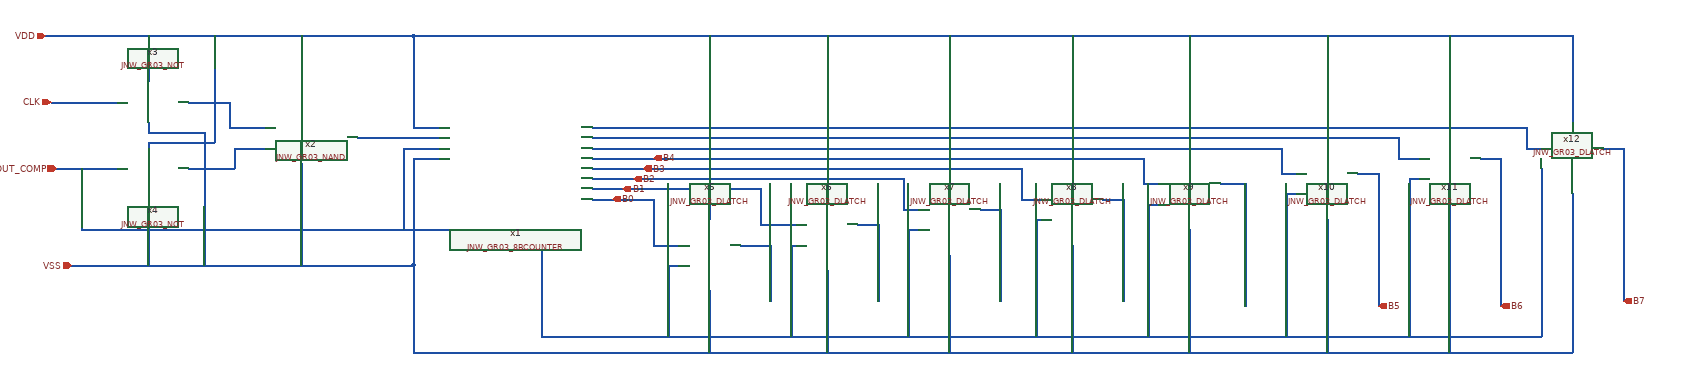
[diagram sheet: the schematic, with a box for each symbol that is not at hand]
v {xschem version=3.4.6 file_version=1.2}
G {}
K {}
V {}
S {}
E {}
N 100 -40 260 -40 {lab=#net1}
N -230 -110 -150 -110 {lab=#net2}
N -150 -110 -150 -60 {lab=#net2}
N -150 -60 -80 -60 {lab=#net2}
N -230 20 -140 20 {lab=#net3}
N -140 -20 -140 20 {lab=#net3}
N -140 -20 -80 -20 {lab=#net3}
N -500 -110 -370 -110 {lab=CLK}
N 210 -60 260 -60 {lab=VDD}
N 210 -240 210 -60 {lab=VDD}
N -510 -240 210 -240 {lab=VDD}
N -310 -240 -310 -150 {lab=VDD}
N -10 -240 -10 -90 {lab=VDD}
N -310 -30 -310 -20 {lab=VDD}
N -310 -30 -180 -30 {lab=VDD}
N -180 -240 -180 -30 {lab=VDD}
N 210 0 260 -0 {lab=VSS}
N 210 0 210 210 {lab=VSS}
N -460 210 210 210 {lab=VSS}
N -310 60 -310 210 {lab=VSS}
N -10 10 -10 210 {lab=VSS}
N -310 -70 -310 -50 {lab=VSS}
N -310 -50 -200 -50 {lab=VSS}
N -200 -50 -200 210 {lab=VSS}
N -490 20 -370 20 {lab=OUT_COMP}
N 560 80 680 80 {lab=B0}
N 680 80 680 170 {lab=B0}
N 680 170 730 170 {lab=B0}
N 560 60 890 60 {lab=B1}
N 850 170 910 170 {lab=#net4}
N 910 170 910 280 {lab=#net4}
N 890 60 890 130 {lab=B1}
N 890 130 960 130 {lab=B1}
N 1080 130 1120 130 {lab=#net5}
N 1120 130 1120 280 {lab=#net5}
N 560 40 1170 40 {lab=B2}
N 1170 40 1170 100 {lab=B2}
N 1170 100 1200 100 {lab=B2}
N 1320 100 1360 100 {lab=#net6}
N 1360 100 1360 280 {lab=#net6}
N 560 20 1400 20 {lab=B3}
N 1400 20 1400 80 {lab=B3}
N 1400 80 1440 80 {lab=B3}
N 1560 80 1600 80 {lab=#net7}
N 1600 80 1600 280 {lab=#net7}
N 560 -0 1640 0 {lab=#net8}
N 1640 0 1640 50 {lab=#net8}
N 1640 50 1670 50 {lab=#net8}
N 1790 50 1840 50 {lab=B4}
N 1840 50 1840 290 {lab=B4}
N 560 -20 1910 -20 {lab=#net9}
N 1910 -20 1910 30 {lab=#net9}
N 1910 30 1940 30 {lab=#net9}
N 2060 30 2100 30 {lab=B5}
N 2100 30 2100 290 {lab=B5}
N 560 -40 2140 -40 {lab=#net10}
N 2140 -40 2140 -0 {lab=#net10}
N 2140 -0 2180 -0 {lab=#net10}
N 2300 0 2340 0 {lab=B6}
N 2340 0 2340 290 {lab=B6}
N 560 -60 2390 -60 {lab=#net11}
N 2390 -60 2390 -20 {lab=#net11}
N 2390 -20 2420 -20 {lab=#net11}
N 2540 -20 2580 -20 {lab=B7}
N 2580 -20 2580 280 {lab=B7}
N 2480 -240 2480 -70 {lab=VDD}
N 210 -240 2480 -240 {lab=VDD}
N 790 -240 790 120 {lab=VDD}
N 1020 -240 1020 80 {lab=VDD}
N 1260 -240 1260 50 {lab=VDD}
N 1500 -240 1500 30 {lab=VDD}
N 1730 -240 1730 -0 {lab=VDD}
N 2000 -240 2000 -20 {lab=VDD}
N 2240 -240 2240 -50 {lab=VDD}
N 210 210 210 380 {lab=VSS}
N 2480 70 2480 380 {lab=VSS}
N 210 380 2480 380 {lab=VSS}
N 790 260 790 380 {lab=VSS}
N 1020 220 1020 380 {lab=VSS}
N 1260 190 1260 380 {lab=VSS}
N 1500 170 1500 380 {lab=VSS}
N 1730 140 1730 380 {lab=VSS}
N 2000 120 2000 380 {lab=VSS}
N 2240 90 2240 380 {lab=VSS}
N -440 20 -440 140 {lab=OUT_COMP}
N -440 140 460 140 {lab=OUT_COMP}
N 460 140 460 320 {lab=OUT_COMP}
N 460 320 460 350 {lab=OUT_COMP}
N 2420 20 2420 350 {lab=OUT_COMP}
N 460 350 2420 350 {lab=OUT_COMP}
N 710 210 730 210 {lab=OUT_COMP}
N 710 210 710 350 {lab=OUT_COMP}
N 950 170 960 170 {lab=OUT_COMP}
N 950 170 950 350 {lab=OUT_COMP}
N 1180 140 1200 140 {lab=OUT_COMP}
N 1180 140 1180 350 {lab=OUT_COMP}
N 1430 120 1440 120 {lab=OUT_COMP}
N 1430 120 1430 350 {lab=OUT_COMP}
N 1650 90 1670 90 {lab=OUT_COMP}
N 1650 90 1650 350 {lab=OUT_COMP}
N 1920 70 1940 70 {lab=OUT_COMP}
N 1920 70 1920 350 {lab=OUT_COMP}
N 2160 40 2180 40 {lab=OUT_COMP}
N 2160 40 2160 350 {lab=OUT_COMP}
N 190 -20 260 -20 {lab=OUT_COMP}
N 190 -20 190 140 {lab=OUT_COMP}
C {devices/ipin.sym} -510 -240 0 0 {name=p1 lab=VDD}
C {devices/ipin.sym} -460 210 0 0 {name=p2 lab=VSS}
C {devices/ipin.sym} -490 20 0 0 {name=p3 lab=OUT_COMP}
C {devices/ipin.sym} -500 -110 0 0 {name=p4 lab=CLK}
C {JNW_GR03_SKY130A/JNW_GR03_8BCOUNTER.sym} 410 10 0 0 {name=x1}
C {JNW_GR03_SKY130A/JNW_GR03_NAND.sym} -60 -40 0 0 {name=x2}
C {JNW_GR03_SKY130A/JNW_GR03_NOT.sym} -350 -110 0 0 {name=x3}
C {JNW_GR03_SKY130A/JNW_GR03_NOT.sym} -350 20 0 0 {name=x4}
C {JNW_GR03_SKY130A/JNW_GR03_DLATCH.sym} 750 190 0 0 {name=x5}
C {devices/opin.sym} 600 80 1 0 {name=p5 lab=B0}
C {JNW_GR03_SKY130A/JNW_GR03_DLATCH.sym} 980 150 0 0 {name=x6}
C {devices/opin.sym} 620 60 1 0 {name=p6 lab=B1}
C {JNW_GR03_SKY130A/JNW_GR03_DLATCH.sym} 1220 120 0 0 {name=x7}
C {devices/opin.sym} 640 40 1 0 {name=p7 lab=B2}
C {JNW_GR03_SKY130A/JNW_GR03_DLATCH.sym} 1460 100 0 0 {name=x8}
C {devices/opin.sym} 660 20 1 0 {name=p8 lab=B3}
C {JNW_GR03_SKY130A/JNW_GR03_DLATCH.sym} 1690 70 0 0 {name=x9}
C {devices/opin.sym} 680 0 1 0 {name=p9 lab=B4}
C {JNW_GR03_SKY130A/JNW_GR03_DLATCH.sym} 1960 50 0 0 {name=x10}
C {devices/opin.sym} 2100 290 1 0 {name=p10 lab=B5}
C {JNW_GR03_SKY130A/JNW_GR03_DLATCH.sym} 2200 20 0 0 {name=x11}
C {devices/opin.sym} 2340 290 1 0 {name=p11 lab=B6}
C {JNW_GR03_SKY130A/JNW_GR03_DLATCH.sym} 2440 0 0 0 {name=x12}
C {devices/opin.sym} 2580 280 1 0 {name=p12 lab=B7}
